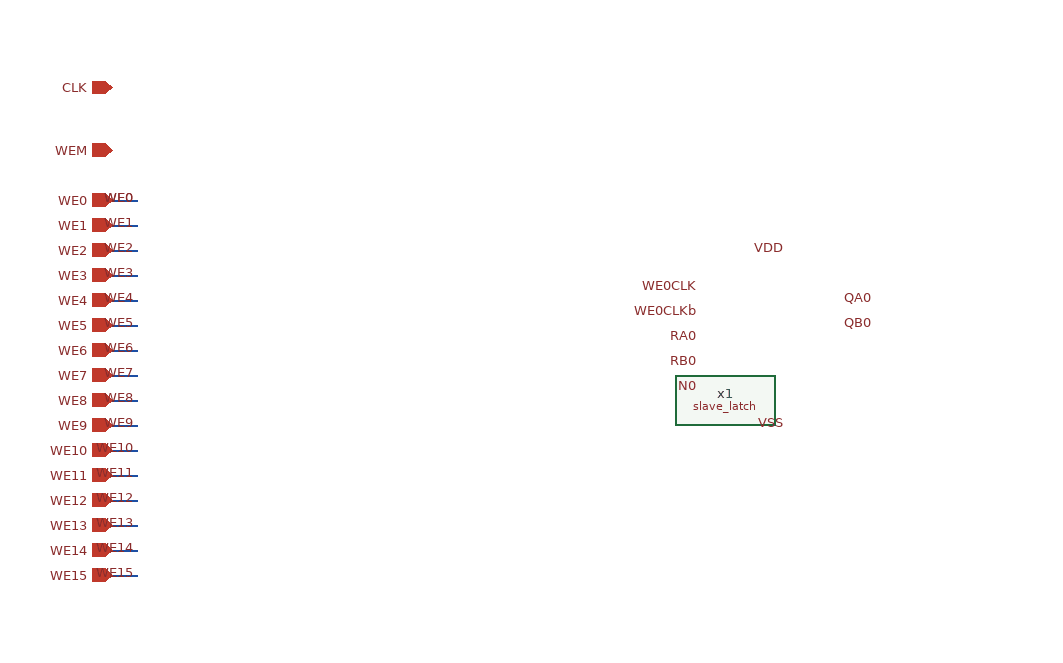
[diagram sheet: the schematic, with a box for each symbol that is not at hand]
v {xschem version=3.4.7 file_version=1.2}
G {}
K {}
V {}
S {}
E {}
N 140 -780 160 -780 {lab=WE0}
N 140 -760 160 -760 {lab=WE1}
N 140 -740 160 -740 {lab=WE2}
N 140 -720 160 -720 {lab=WE3}
N 140 -700 160 -700 {lab=WE4}
N 140 -680 160 -680 {lab=WE5}
N 140 -660 160 -660 {lab=WE6}
N 140 -640 160 -640 {lab=WE7}
N 140 -620 160 -620 {lab=WE8}
N 140 -600 160 -600 {lab=WE9}
N 140 -580 160 -580 {lab=WE10}
N 140 -560 160 -560 {lab=WE11}
N 140 -540 160 -540 {lab=WE12}
N 140 -520 160 -520 {lab=WE13}
N 140 -500 160 -500 {lab=WE14}
N 140 -480 160 -480 {lab=WE15}
C {ipin.sym} 140 -870 0 0 {name=p1 lab=CLK}
C {ipin.sym} 140 -820 0 0 {name=p2 lab=WEM}
C {ipin.sym} 140 -780 0 0 {name=p3 lab=WE0}
C {ipin.sym} 140 -760 0 0 {name=p4 lab=WE1}
C {lab_wire.sym} 160 -780 0 0 {name=p5 sig_type=std_logic lab=WE0}
C {lab_wire.sym} 160 -760 0 0 {name=p6 sig_type=std_logic lab=WE1}
C {ipin.sym} 140 -740 0 0 {name=p7 lab=WE2}
C {ipin.sym} 140 -720 0 0 {name=p8 lab=WE3}
C {lab_wire.sym} 160 -740 0 0 {name=p9 sig_type=std_logic lab=WE2}
C {lab_wire.sym} 160 -720 0 0 {name=p10 sig_type=std_logic lab=WE3}
C {ipin.sym} 140 -700 0 0 {name=p11 lab=WE4}
C {ipin.sym} 140 -680 0 0 {name=p12 lab=WE5}
C {lab_wire.sym} 160 -700 0 0 {name=p13 sig_type=std_logic lab=WE4}
C {lab_wire.sym} 160 -680 0 0 {name=p14 sig_type=std_logic lab=WE5}
C {ipin.sym} 140 -660 0 0 {name=p15 lab=WE6}
C {ipin.sym} 140 -640 0 0 {name=p16 lab=WE7}
C {lab_wire.sym} 160 -660 0 0 {name=p17 sig_type=std_logic lab=WE6}
C {lab_wire.sym} 160 -640 0 0 {name=p18 sig_type=std_logic lab=WE7}
C {ipin.sym} 140 -620 0 0 {name=p19 lab=WE8}
C {ipin.sym} 140 -600 0 0 {name=p20 lab=WE9}
C {lab_wire.sym} 160 -620 0 0 {name=p21 sig_type=std_logic lab=WE8}
C {lab_wire.sym} 160 -600 0 0 {name=p22 sig_type=std_logic lab=WE9}
C {ipin.sym} 140 -580 0 0 {name=p23 lab=WE10}
C {ipin.sym} 140 -560 0 0 {name=p24 lab=WE11}
C {lab_wire.sym} 160 -580 0 0 {name=p25 sig_type=std_logic lab=WE10}
C {lab_wire.sym} 160 -560 0 0 {name=p26 sig_type=std_logic lab=WE11}
C {ipin.sym} 140 -540 0 0 {name=p27 lab=WE12}
C {ipin.sym} 140 -520 0 0 {name=p28 lab=WE13}
C {lab_wire.sym} 160 -540 0 0 {name=p29 sig_type=std_logic lab=WE12}
C {lab_wire.sym} 160 -520 0 0 {name=p30 sig_type=std_logic lab=WE13}
C {ipin.sym} 140 -500 0 0 {name=p31 lab=WE14}
C {ipin.sym} 140 -480 0 0 {name=p32 lab=WE15}
C {lab_wire.sym} 160 -500 0 0 {name=p33 sig_type=std_logic lab=WE14}
C {lab_wire.sym} 160 -480 0 0 {name=p34 sig_type=std_logic lab=WE15}
C {engn1600-team1/CAD3/slave_latch.sym} 630 -620 0 0 {name=x1}
C {lab_wire.sym} 160 -780 0 0 {name=p35 sig_type=std_logic lab=WE0}
C {lab_wire.sym} 610 -710 0 0 {name=p36 sig_type=std_logic lab=WE0CLK}
C {lab_wire.sym} 610 -690 0 0 {name=p37 sig_type=std_logic lab=WE0CLKb}
C {lab_wire.sym} 610 -670 0 0 {name=p38 sig_type=std_logic lab=RA0}
C {lab_wire.sym} 610 -650 0 0 {name=p39 sig_type=std_logic lab=RB0}
C {lab_wire.sym} 610 -630 0 0 {name=p40 sig_type=std_logic lab=N0}
C {lab_wire.sym} 680 -740 0 0 {name=p41 sig_type=std_logic lab=VDD}
C {lab_wire.sym} 680 -600 0 0 {name=p42 sig_type=std_logic lab=VSS}
C {lab_wire.sym} 750 -700 0 0 {name=p43 sig_type=std_logic lab=QA0}
C {lab_wire.sym} 750 -680 0 0 {name=p44 sig_type=std_logic lab=QB0}
